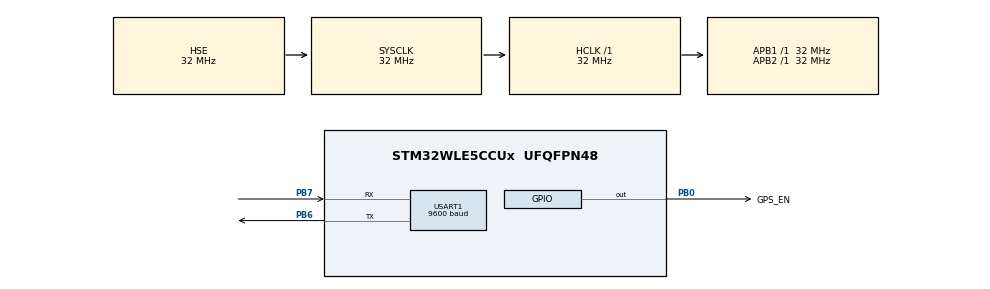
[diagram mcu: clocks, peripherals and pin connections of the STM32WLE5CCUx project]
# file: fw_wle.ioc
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FREERTOS.HEAP_NUMBER=3
FREERTOS.Tasks01=Running_Actor,8,128,Active_EventLoop,Default,NULL,Dynamic,NULL,NULL
FREERTOS.configCHECK_FOR_STACK_OVERFLOW=2
FREERTOS.configGENERATE_RUN_TIME_STATS=1
FREERTOS.configRECORD_STACK_HIGH_ADDRESS=1
FREERTOS.configUSE_IDLE_HOOK=1
FREERTOS.configUSE_MALLOC_FAILED_HOOK=1
FREERTOS.configUSE_STATS_FORMATTING_FUNCTIONS=1
FREERTOS.configUSE_TICK_HOOK=1
Mcu.Family=STM32WL
Mcu.Name=STM32WLE5CCUx
Mcu.Package=UFQFPN48
NVIC.PriorityGroup=NVIC_PRIORITYGROUP_4
NVIC.TIM16_IRQn=true\:5\:0\:false\:false\:true\:true\:true\:true
OSC_IN.Mode=HSE-External-Oscillator
OSC_IN.Signal=RCC_OSC_IN
OSC_OUT.Mode=HSE-External-Oscillator
OSC_OUT.Signal=RCC_OSC_OUT
PB0-VDD_TCXO.GPIO_Label=GPS_EN
PB0-VDD_TCXO.GPIO_PuPd=GPIO_PULLDOWN
PB0-VDD_TCXO.Signal=GPIO_Output
PB6.Mode=Asynchronous
PB6.Signal=USART1_TX
PB7.Mode=Asynchronous
PB7.Signal=USART1_RX
PC14-OSC32_IN.Mode=LSE-External-Oscillator
PC14-OSC32_IN.Signal=RCC_OSC32_IN
PC15-OSC32_OUT.Mode=LSE-External-Oscillator
PC15-OSC32_OUT.Signal=RCC_OSC32_OUT
ProjectManager.HeapSize=0x200
ProjectManager.StackSize=0x400
ProjectManager.TargetToolchain=STM32CubeIDE
RCC.AHBFreq_Value=32000000
RCC.APB1Freq_Value=32000000
RCC.APB1TimFreq_Value=32000000
RCC.APB2Freq_Value=32000000
RCC.APB2TimFreq_Value=32000000
RCC.APB3Freq_Value=32000000
RCC.CortexFreq_Value=32000000
RCC.HCLKFreq_Value=32000000
RCC.HSE_VALUE=32000000
RCC.HSI_VALUE=16000000
RCC.LSE_VALUE=32768
RCC.SYSCLKFreq_VALUE=32000000
RCC.SYSCLKSource=RCC_SYSCLKSOURCE_HSE
RCC.VCOOutputFreq_Value=32000000
TIM16.Period=32-1
USART1.BaudRate=9600
USART1.VirtualMode-Asynchronous=VM_ASYNC
VP_FREERTOS_VS_CMSIS_V2.Mode=CMSIS_V2
VP_TIM16_VS_ClockSourceINT.Mode=Enable_Timer
board=custom

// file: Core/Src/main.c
/* USER CODE BEGIN Header */
/**
 ******************************************************************************
 * @file           : main.c
 * @brief          : Main program body
 ******************************************************************************
 * @attention
 *
 * Copyright (c) 2021 STMicroelectronics.
 * All rights reserved.
 *
 * This software is licensed under terms that can be found in the LICENSE file
 * in the root directory of this software component.
 * If no LICENSE file comes with this software, it is provided AS-IS.
 *
 ******************************************************************************
 */
/* USER CODE END Header */
#include "main.h"
#include "cmsis_os.h"

/* USER CODE BEGIN Includes */
#include "string.h"
#include "stdio.h"
#include "stdbool.h"
/* USER CODE END Includes */

/* USER CODE BEGIN PTD */
typedef enum eTestStatus
{
	RET_FAIL=0,
	RET_OK,
	RET_TIMEOUT
}eTestStatus;
eTestStatus GPS_test;
/* USER CODE END PTD */

/* USER CODE BEGIN PD */
#define SYS_ACTOR_EQUEUE_LEN				10
/* USER CODE END PD */

TIM_HandleTypeDef htim16;

UART_HandleTypeDef huart1;

/* Definitions for DefaultTask */
osThreadId_t DefaultTaskHandle;
const osThreadAttr_t DefaultTask_attributes = {
		.name = "DefaultTask",
		.priority = (osPriority_t) osPriorityLow,
		.stack_size = 768 * 4
};
/* USER CODE BEGIN PV */
unsigned long ulHighFrequencyTimerTicks;

/***************************************************************************************************/
/* System active objects --------------------------------------------------------------*/
/* Definitions for Running_Actor */
const osThreadAttr_t Sys_ThreadParam = {
		.name = 	"Sys_Actor",
		.priority = (osPriority_t) osPriorityLow1,
		.cb_mem = NULL, /*  Automatic Dynamic Allocation */
		.stack_size = (4*1024)
};

const osMessageQueueAttr_t Sys_EQueueParam = {
		.name = "Sys_Actor",
		.cb_mem = NULL, /*  Automatic Dynamic Allocation */
};

Active Actor_Sys;

/***************************************************************************************************/
/* USER CODE END PV */

void SystemClock_Config(void);
static void MX_GPIO_Init(void);
static void MX_USART1_UART_Init(void);
static void MX_TIM16_Init(void);
void Default_Task(void *argument);

/* USER CODE BEGIN PFP */
static eStatus Sys_StateRunning(StateMachine_t* const me, const EvtId_t p_event);
static eStatus Sys_StateSleep(StateMachine_t* const me, const EvtId_t p_event);

/* USER CODE END PFP */

/* USER CODE BEGIN 0 */

#if TEST_FRAMEWORK
volatile uint8_t  g_ui8_test=1;

typedef struct
{
	Evt super;
	char imvip[10];
}test_evt;
#endif  /* End of !TEST */

/* USER CODE END 0 */

int main(void)
{

	/* MCU Configuration--------------------------------------------------------*/

	/* Reset of all peripherals, Initializes the Flash interface and the Systick. */
	HAL_Init();

	/* Configure the system clock */
	SystemClock_Config();

	/* Initialize all configured peripherals */
	MX_GPIO_Init();
	MX_USART1_UART_Init();
	MX_TIM16_Init();

	/* Init scheduler */
	osKernelInitialize();
	configureTimerForRunTimeStats();

	/* Create the thread(s) */
	/* creation of DefaultTask */
	DefaultTaskHandle = osThreadNew(Default_Task, NULL, &DefaultTask_attributes);

	/* USER CODE BEGIN RTOS_THREADS */
	Mempool_Init();
	Active_Init(&Actor_Sys, &Sys_StateRunning, &Sys_ThreadParam, &Sys_EQueueParam, SYS_ACTOR_EQUEUE_LEN);
	/* add threads, ... */
	/* USER CODE END RTOS_THREADS */

	/* Start scheduler */
	osKernelStart();

	/* We should never get here as control is now taken by the scheduler */
	/* Infinite loop */
	while (1)
	{

	}
}

void SystemClock_Config(void)
{
	RCC_OscInitTypeDef RCC_OscInitStruct = {0};
	RCC_ClkInitTypeDef RCC_ClkInitStruct = {0};

	/** Configure the main internal regulator output voltage
	 */
	__HAL_PWR_VOLTAGESCALING_CONFIG(PWR_REGULATOR_VOLTAGE_SCALE1);
	/** Initializes the CPU, AHB and APB busses clocks
	 */
	RCC_OscInitStruct.OscillatorType = RCC_OSCILLATORTYPE_HSE;
	RCC_OscInitStruct.HSEState = RCC_HSE_ON;
	RCC_OscInitStruct.HSEDiv = RCC_HSE_DIV1;
	RCC_OscInitStruct.PLL.PLLState = RCC_PLL_NONE;
	if (HAL_RCC_OscConfig(&RCC_OscInitStruct) != HAL_OK)
	{
		Error_Handler();
	}
	/** Configure the SYSCLKSource, HCLK, PCLK1 and PCLK2 clocks dividers
	 */
	RCC_ClkInitStruct.ClockType = RCC_CLOCKTYPE_HCLK3|RCC_CLOCKTYPE_HCLK
			|RCC_CLOCKTYPE_SYSCLK|RCC_CLOCKTYPE_PCLK1
			|RCC_CLOCKTYPE_PCLK2;
	RCC_ClkInitStruct.SYSCLKSource = RCC_SYSCLKSOURCE_HSE;
	RCC_ClkInitStruct.AHBCLKDivider = RCC_SYSCLK_DIV1;
	RCC_ClkInitStruct.APB1CLKDivider = RCC_HCLK_DIV1;
	RCC_ClkInitStruct.APB2CLKDivider = RCC_HCLK_DIV1;
	RCC_ClkInitStruct.AHBCLK3Divider = RCC_SYSCLK_DIV1;

	if (HAL_RCC_ClockConfig(&RCC_ClkInitStruct, FLASH_LATENCY_1) != HAL_OK)
	{
		Error_Handler();
	}
}

static void MX_TIM16_Init(void)
{

	htim16.Instance = TIM16;
	htim16.Init.Prescaler = 0;
	htim16.Init.CounterMode = TIM_COUNTERMODE_UP;
	htim16.Init.Period = 1600-1;
	htim16.Init.ClockDivision = TIM_CLOCKDIVISION_DIV1;
	htim16.Init.RepetitionCounter = 0;
	htim16.Init.AutoReloadPreload = TIM_AUTORELOAD_PRELOAD_DISABLE;
	if (HAL_TIM_Base_Init(&htim16) != HAL_OK)
	{
		Error_Handler();
	}

}

static void MX_USART1_UART_Init(void)
{

	huart1.Instance = USART1;
	huart1.Init.BaudRate = 9600;
	huart1.Init.WordLength = UART_WORDLENGTH_8B;
	huart1.Init.StopBits = UART_STOPBITS_1;
	huart1.Init.Parity = UART_PARITY_NONE;
	huart1.Init.Mode = UART_MODE_TX_RX;
	huart1.Init.HwFlowCtl = UART_HWCONTROL_NONE;
	huart1.Init.OverSampling = UART_OVERSAMPLING_16;
	huart1.Init.OneBitSampling = UART_ONE_BIT_SAMPLE_DISABLE;
	huart1.Init.ClockPrescaler = UART_PRESCALER_DIV1;
	huart1.AdvancedInit.AdvFeatureInit = UART_ADVFEATURE_NO_INIT;
	if (HAL_UART_Init(&huart1) != HAL_OK)
	{
		Error_Handler();
	}
	if (HAL_UARTEx_SetTxFifoThreshold(&huart1, UART_TXFIFO_THRESHOLD_1_8) != HAL_OK)
	{
		Error_Handler();
	}
	if (HAL_UARTEx_SetRxFifoThreshold(&huart1, UART_RXFIFO_THRESHOLD_1_8) != HAL_OK)
	{
		Error_Handler();
	}
	if (HAL_UARTEx_DisableFifoMode(&huart1) != HAL_OK)
	{
		Error_Handler();
	}

}

static void MX_GPIO_Init(void)
{
	GPIO_InitTypeDef GPIO_InitStruct = {0};

	/* GPIO Ports Clock Enable */
	__HAL_RCC_GPIOA_CLK_ENABLE();
	__HAL_RCC_GPIOB_CLK_ENABLE();
	__HAL_RCC_GPIOC_CLK_ENABLE();

	/*Configure GPIO pin Output Level */
	HAL_GPIO_WritePin(GPS_EN_GPIO_Port, GPS_EN_Pin, GPIO_PIN_RESET);

	/*Configure GPIO pin : GPS_EN_Pin */

	GPIO_InitStruct.Pin = GPIO_PIN_11 | GPIO_PIN_12;
	GPIO_InitStruct.Mode = GPIO_MODE_OUTPUT_PP;
	GPIO_InitStruct.Pull = GPIO_PULLDOWN;
	GPIO_InitStruct.Speed = GPIO_SPEED_FREQ_LOW;
	HAL_GPIO_Init(GPIOA, &GPIO_InitStruct);

	GPIO_InitStruct.Pin = GPS_EN_Pin;
	GPIO_InitStruct.Mode = GPIO_MODE_OUTPUT_PP;
	GPIO_InitStruct.Pull = GPIO_PULLDOWN;
	GPIO_InitStruct.Speed = GPIO_SPEED_FREQ_LOW;
	HAL_GPIO_Init(GPS_EN_GPIO_Port, &GPIO_InitStruct);

}

/* USER CODE BEGIN 4 */

static eStatus Sys_StateRunning(StateMachine_t* const me, const EvtId_t p_event)
{
	eStatus status;
	switch (p_event->sig) {
	case SIG_IDLE:
	{
#if TEST_FRAMEWORK

		#if TEST_DYNAMIC
		test_evt* recv_e = p_event;
		if(	recv_e->imvip[0] != 10)
			configASSERT(0);
		#endif  /* End of TEST_DYNAMIC */
#endif  /* End of TEST_FRAMEWORK */

		status = TRANSITION(Sys_StateSleep);
	}
	break;

	case ENTRY_SIG:
	case EXIT_SIG:
	default:
	{
		status = STATUS_IGNORE;
	}
	break;
	}
	return status;
}

static eStatus Sys_StateSleep(StateMachine_t* const me, const EvtId_t p_event)
{
	eStatus status;
	switch (p_event->sig) {
	/*		case value:
		{

		}
		break;		*/

	case ENTRY_SIG:
	case EXIT_SIG:
	default:
	{
		status = STATUS_IGNORE;
	}
	break;
	}
	return status;
}

/* USER CODE END 4 */

/* USER CODE BEGIN 5 */
void Default_Task(void *argument)
{

#if TEST_FRAMEWORK
	#if TEST_DYNAMIC_EVT
	/* ******************************************************* */
	test_evt* test_me = (test_evt*)Event_New(SIG_IDLE, sizeof(test_evt));
	for(uint8_t idx=0; idx<10; idx++)
	{
		test_me->imvip[idx] = idx+10;
	}
	Active_post(&Actor_Sys, test_me);

	/* ******************************************************* */
	#else
	Evt test_me = {
			.sig = SIG_IDLE
	};
	Active_post(&Actor_Sys, &test_me);

	#endif  /* End of TEST_DYNAMIC_EVT */
#endif  /* End of TEST_FRAMEWORK */

	while(1)
	{
		GPIOA->ODR ^= (1<<11);
		HAL_Delay(5);
		if(g_ui8_test >0)
		{
			g_ui8_test--;
		}
		osDelay(5);
	}

}
/* USER CODE END 5 */

void Error_Handler(void)
{
	__disable_irq();
	while (1)
	{
	}
}

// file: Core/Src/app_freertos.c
/* USER CODE BEGIN Header */
/**
  ******************************************************************************
  * File Name          : app_freertos.c
  * Description        : Code for freertos applications
  ******************************************************************************
  * @attention
  *
  * Copyright (c) 2022 STMicroelectronics.
  * All rights reserved.
  *
  * This software is licensed under terms that can be found in the LICENSE file
  * in the root directory of this software component.
  * If no LICENSE file comes with this software, it is provided AS-IS.
  *
  ******************************************************************************
  */
/* USER CODE END Header */

#include "FreeRTOS.h"
#include "task.h"
#include "main.h"

/* USER CODE BEGIN Variables */
extern volatile unsigned long ulHighFrequencyTimerTicks;
extern TIM_HandleTypeDef htim16;

/* USER CODE END Variables */

/* Hook prototypes */
void configureTimerForRunTimeStats(void);
unsigned long getRunTimeCounterValue(void);
void vApplicationIdleHook(void);
void vApplicationTickHook(void);
void vApplicationStackOverflowHook(xTaskHandle xTask, signed char *pcTaskName);
void vApplicationMallocFailedHook(void);

/* USER CODE BEGIN 1 */

/* Functions needed when configGENERATE_RUN_TIME_STATS is on */
__weak void configureTimerForRunTimeStats(void)
{
	ulHighFrequencyTimerTicks = 0;
	HAL_TIM_Base_Start_IT(&htim16);
}

__weak unsigned long getRunTimeCounterValue(void)
{
	return ulHighFrequencyTimerTicks;

}
/* USER CODE END 1 */

/* USER CODE BEGIN 2 */
void vApplicationIdleHook( void )
{
   /* vApplicationIdleHook() will only be called if configUSE_IDLE_HOOK is set
   to 1 in FreeRTOSConfig.h. It will be called on each iteration of the idle
   task. It is essential that code added to this hook function never attempts
   to block in any way (for example, call xQueueReceive() with a block time
   specified, or call vTaskDelay()). If the application makes use of the
   vTaskDelete() API function (as this demo application does) then it is also
   important that vApplicationIdleHook() is permitted to return to its calling
   function, because it is the responsibility of the idle task to clean up
   memory allocated by the kernel to any task that has since been deleted. */

}
/* USER CODE END 2 */

/* USER CODE BEGIN 3 */
void vApplicationTickHook( void )
{
   /* This function will be called by each tick interrupt if
   configUSE_TICK_HOOK is set to 1 in FreeRTOSConfig.h. User code can be
   added here, but the tick hook is called from an interrupt context, so
   code must not attempt to block, and only the interrupt safe FreeRTOS API
   functions can be used (those that end in FromISR()). */
}
/* USER CODE END 3 */

/* USER CODE BEGIN 4 */
void vApplicationStackOverflowHook(xTaskHandle xTask, signed char *pcTaskName)
{
	assert_param(0);

   /* Run time stack overflow checking is performed if
   configCHECK_FOR_STACK_OVERFLOW is defined to 1 or 2. This hook function is
   called if a stack overflow is detected. */
}
/* USER CODE END 4 */

/* USER CODE BEGIN 5 */
void vApplicationMallocFailedHook(void)
{
	assert_param(0);
   /* vApplicationMallocFailedHook() will only be called if
   configUSE_MALLOC_FAILED_HOOK is set to 1 in FreeRTOSConfig.h. It is a hook
   function that will get called if a call to pvPortMalloc() fails.
   pvPortMalloc() is called internally by the kernel whenever a task, queue,
   timer or semaphore is created. It is also called by various parts of the
   demo application. If heap_1.c or heap_2.c are used, then the size of the
   heap available to pvPortMalloc() is defined by configTOTAL_HEAP_SIZE in
   FreeRTOSConfig.h, and the xPortGetFreeHeapSize() API function can be used
   to query the size of free heap space that remains (although it does not
   provide information on how the remaining heap might be fragmented). */
}
/* USER CODE END 5 */
